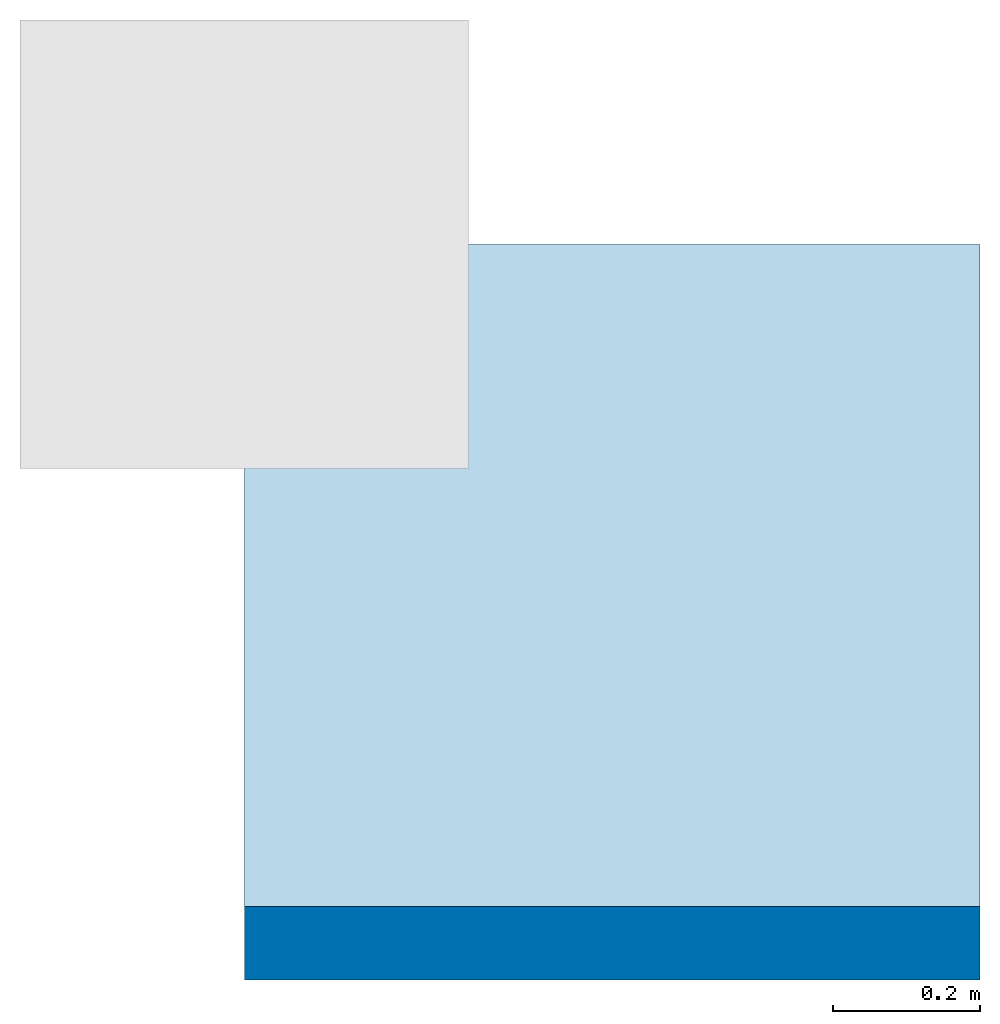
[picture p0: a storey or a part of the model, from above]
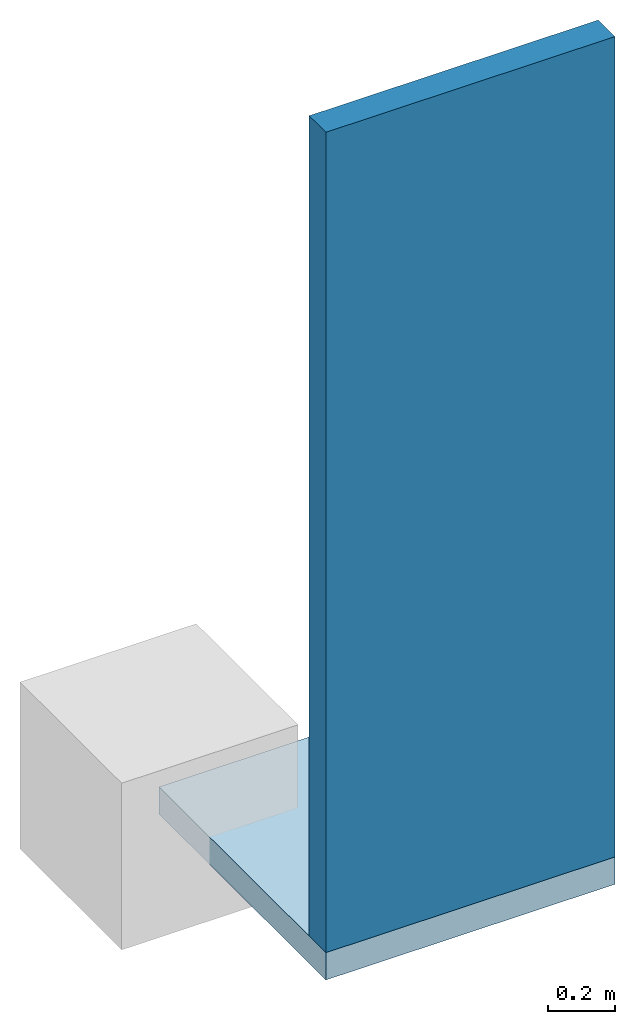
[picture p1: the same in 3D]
Properties of the parts of a building model (IFC4)

# File
Description: ViewDefinition[DesignTransferView]
File name: external style.ifc
Time: 2024-12-01T14:44:13-06:00
Written by: IfcOpenShell 0.0.0
Made in: Bonsai 0.8.1-alpha241112-e3317af
Authorization: Nobody

# IfcActuator, Cube
In: My Storey
PredefinedType: ELECTRICACTUATOR; Material: Test Material

# IfcSlab: TYPEX, Slab
In: My Storey
Type - PredefinedType: FLOOR; Material: Test Material 0.328084 ft
Type - EPset_Parametric - LayerSetDirection: AXIS3
EPset_Parametric - Engine: Bonsai.DumbLayer3

# IfcWall: TYPEX, Wall
In: My Storey
Type - PredefinedType: SOLIDWALL; Material: Test Material 0.328084 ft
Type - EPset_Parametric - LayerSetDirection: AXIS2
EPset_Parametric - Engine: Bonsai.DumbLayer2
